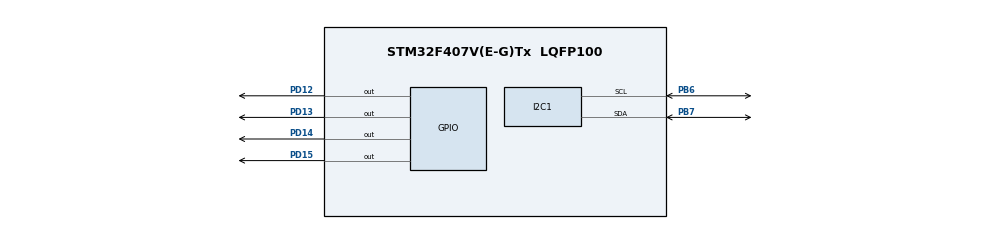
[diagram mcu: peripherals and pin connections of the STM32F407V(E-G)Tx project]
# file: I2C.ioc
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Mcu.Family=STM32F4
Mcu.Name=STM32F407V(E-G)Tx
Mcu.Package=LQFP100
NVIC.PriorityGroup=NVIC_PRIORITYGROUP_4
PB6.Mode=I2C
PB6.Signal=I2C1_SCL
PB7.Mode=I2C
PB7.Signal=I2C1_SDA
PD12.Signal=GPIO_Output
PD13.Signal=GPIO_Output
PD14.Signal=GPIO_Output
PD15.Signal=GPIO_Output
ProjectManager.HeapSize=0x200
ProjectManager.StackSize=0x400
ProjectManager.TargetToolchain=MDK-ARM V5.27
RCC.AHBFreq_Value=16000000
RCC.APB1Freq_Value=16000000
RCC.APB2Freq_Value=16000000
RCC.CortexFreq_Value=16000000
RCC.HSE_VALUE=25000000
RCC.HSI_VALUE=16000000
RCC.LSE_VALUE=32768
RCC.SYSCLKFreq_VALUE=16000000
RCC.VCOOutputFreq_Value=192000000
board=custom

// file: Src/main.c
/* USER CODE BEGIN Header */
/**
  ******************************************************************************
  * @file           : main.c
  * @brief          : Main program body
  ******************************************************************************
  * @attention
  *
  * <h2><center>&copy; Copyright (c) 2020 STMicroelectronics.
  * All rights reserved.</center></h2>
  *
  * This software component is licensed by ST under BSD 3-Clause license,
  * the "License"; You may not use this file except in compliance with the
  * License. You may obtain a copy of the License at:
  *                        opensource.org/licenses/BSD-3-Clause
  *
  ******************************************************************************
  */
/* USER CODE END Header */

#include "main.h"

/* USER CODE BEGIN Includes */

#define mpu6050Address 0x68
/* USER CODE END Includes */

I2C_HandleTypeDef hi2c1;

void SystemClock_Config(void);
static void MX_GPIO_Init(void);
static void MX_I2C1_Init(void);

/* USER CODE BEGIN 0 */
uint8_t i2cBuf[8];
uint8_t i2cBif[8];
int16_t ax,ay,az;
float Xaccel, Yaccel, Zaccel;
/* USER CODE END 0 */

int main(void)
{

  /* MCU Configuration--------------------------------------------------------*/

  /* Reset of all peripherals, Initializes the Flash interface and the Systick. */
  HAL_Init();

  /* Configure the system clock */
  SystemClock_Config();

  /* Initialize all configured peripherals */
  MX_GPIO_Init();
  MX_I2C1_Init();
  /* USER CODE BEGIN 2 */

//	//1. Scan the I2C addresses
//	/*for(uint8_t i=0; i<255; i++){
//		if(HAL_I2C_IsDeviceReady(&hi2c1, i, 1, 10) == HAL_OK){
//			HAL_GPIO_TogglePin(GPIOD, L1_Pin);
//			break;
//		}
//	}*/
	uint8_t mpuArss;
	mpuArss = (mpu6050Address<<1);
	//2. I2C write example
	//a) set accelerometer range (reg28)
	i2cBuf[0] = 28;			//register address: Accelerometer config 1
	i2cBuf[1] = 0x08;		//Data to write, +-4g range
	HAL_I2C_Master_Transmit(&hi2c1, mpuArss, i2cBuf, 2, 10);

	//3. I2C Read example
	//Request to read from a register (reg28)
	i2cBuf[0] = 28;			//register address: Accelerometer config 1
	HAL_I2C_Master_Transmit(&hi2c1, mpuArss,i2cBuf, 1, 10);

	//Read data
	i2cBuf[1] = 0x03;
	HAL_I2C_Master_Receive(&hi2c1, mpuArss|0x01, &i2cBuf[1], 1, 10);

//
//	I2C_Read(0x17, i2cBif, 1);
//1. Initialise the MPU6050 module and I2C

  /* USER CODE END 2 */

  /* Infinite loop */
  while (1)
  {

    /* USER CODE BEGIN 3 */
	/*	MPU6050_Get_Accel_Scale(&myAccelScaled);
		MPU6050_Get_Gyro_Scale(&myGyroScaled);

		HAL_GPIO_TogglePin(GPIOD, L2_Pin);
		HAL_Delay(10);*/
		//4. Read accelerometer daya
		//Request to read from a register
		//i2cBuf[0] = 0x3B;			//Register address: X_axis H
		//HAL_I2C_Master_Transmit(&hi2c1, mpuArss, i2cBuf, 1, 10);
		//Read data
		//i2cBuf[1] = 0x06;
		//HAL_I2C_Master_Receive(&hi2c1, mpuArss, &i2cBuf[1], 6, 10);

  }
  /* USER CODE END 3 */
}

void SystemClock_Config(void)
{
  RCC_OscInitTypeDef RCC_OscInitStruct = {0};
  RCC_ClkInitTypeDef RCC_ClkInitStruct = {0};

  /** Configure the main internal regulator output voltage
  */
  __HAL_RCC_PWR_CLK_ENABLE();
  __HAL_PWR_VOLTAGESCALING_CONFIG(PWR_REGULATOR_VOLTAGE_SCALE1);
  /** Initializes the CPU, AHB and APB busses clocks
  */
  RCC_OscInitStruct.OscillatorType = RCC_OSCILLATORTYPE_HSI;
  RCC_OscInitStruct.HSIState = RCC_HSI_ON;
  RCC_OscInitStruct.HSICalibrationValue = RCC_HSICALIBRATION_DEFAULT;
  RCC_OscInitStruct.PLL.PLLState = RCC_PLL_ON;
  RCC_OscInitStruct.PLL.PLLSource = RCC_PLLSOURCE_HSI;
  RCC_OscInitStruct.PLL.PLLM = 8;
  RCC_OscInitStruct.PLL.PLLN = 168;
  RCC_OscInitStruct.PLL.PLLP = RCC_PLLP_DIV2;
  RCC_OscInitStruct.PLL.PLLQ = 4;
  if (HAL_RCC_OscConfig(&RCC_OscInitStruct) != HAL_OK)
  {
    Error_Handler();
  }
  /** Initializes the CPU, AHB and APB busses clocks
  */
  RCC_ClkInitStruct.ClockType = RCC_CLOCKTYPE_HCLK|RCC_CLOCKTYPE_SYSCLK
                              |RCC_CLOCKTYPE_PCLK1|RCC_CLOCKTYPE_PCLK2;
  RCC_ClkInitStruct.SYSCLKSource = RCC_SYSCLKSOURCE_PLLCLK;
  RCC_ClkInitStruct.AHBCLKDivider = RCC_SYSCLK_DIV1;
  RCC_ClkInitStruct.APB1CLKDivider = RCC_HCLK_DIV4;
  RCC_ClkInitStruct.APB2CLKDivider = RCC_HCLK_DIV2;

  if (HAL_RCC_ClockConfig(&RCC_ClkInitStruct, FLASH_LATENCY_5) != HAL_OK)
  {
    Error_Handler();
  }
}

static void MX_I2C1_Init(void)
{

  hi2c1.Instance = I2C1;
  hi2c1.Init.ClockSpeed = 100000;
  hi2c1.Init.DutyCycle = I2C_DUTYCYCLE_2;
  hi2c1.Init.OwnAddress1 = 0;
  hi2c1.Init.AddressingMode = I2C_ADDRESSINGMODE_7BIT;
  hi2c1.Init.DualAddressMode = I2C_DUALADDRESS_DISABLE;
  hi2c1.Init.OwnAddress2 = 0;
  hi2c1.Init.GeneralCallMode = I2C_GENERALCALL_DISABLE;
  hi2c1.Init.NoStretchMode = I2C_NOSTRETCH_DISABLE;
  if (HAL_I2C_Init(&hi2c1) != HAL_OK)
  {
    Error_Handler();
  }

}

static void MX_GPIO_Init(void)
{
  GPIO_InitTypeDef GPIO_InitStruct = {0};

  /* GPIO Ports Clock Enable */
  __HAL_RCC_GPIOD_CLK_ENABLE();
  __HAL_RCC_GPIOA_CLK_ENABLE();
  __HAL_RCC_GPIOB_CLK_ENABLE();

  /*Configure GPIO pin Output Level */
  HAL_GPIO_WritePin(GPIOD, GPIO_PIN_12|GPIO_PIN_13|GPIO_PIN_14|GPIO_PIN_15, GPIO_PIN_RESET);

  /*Configure GPIO pins : L1_Pin L2_Pin L3_Pin L4_Pin */
  GPIO_InitStruct.Pin = GPIO_PIN_12|GPIO_PIN_13|GPIO_PIN_14|GPIO_PIN_15;
  GPIO_InitStruct.Mode = GPIO_MODE_OUTPUT_PP;
  GPIO_InitStruct.Pull = GPIO_NOPULL;
  GPIO_InitStruct.Speed = GPIO_SPEED_FREQ_LOW;
  HAL_GPIO_Init(GPIOD, &GPIO_InitStruct);

}

void Error_Handler(void)
{
}

/************************ (C) COPYRIGHT STMicroelectronics *****END OF FILE****/
